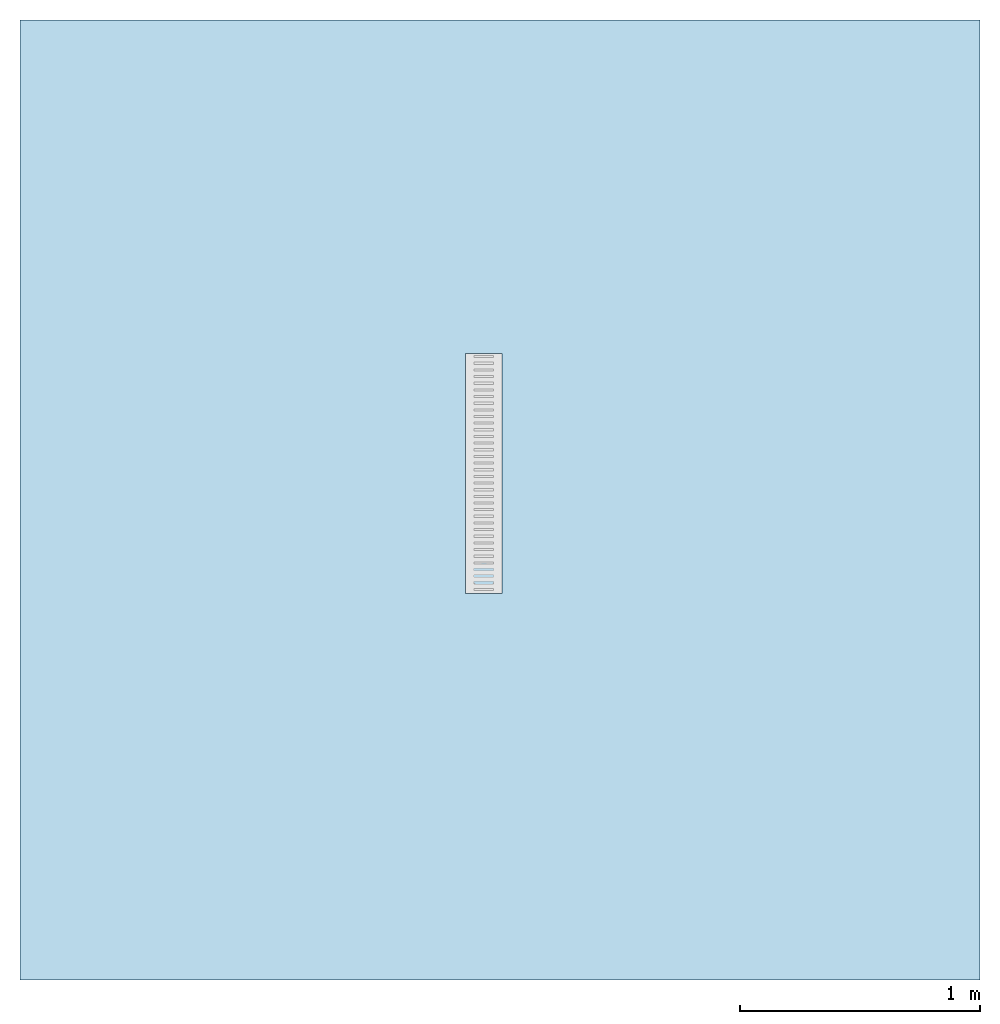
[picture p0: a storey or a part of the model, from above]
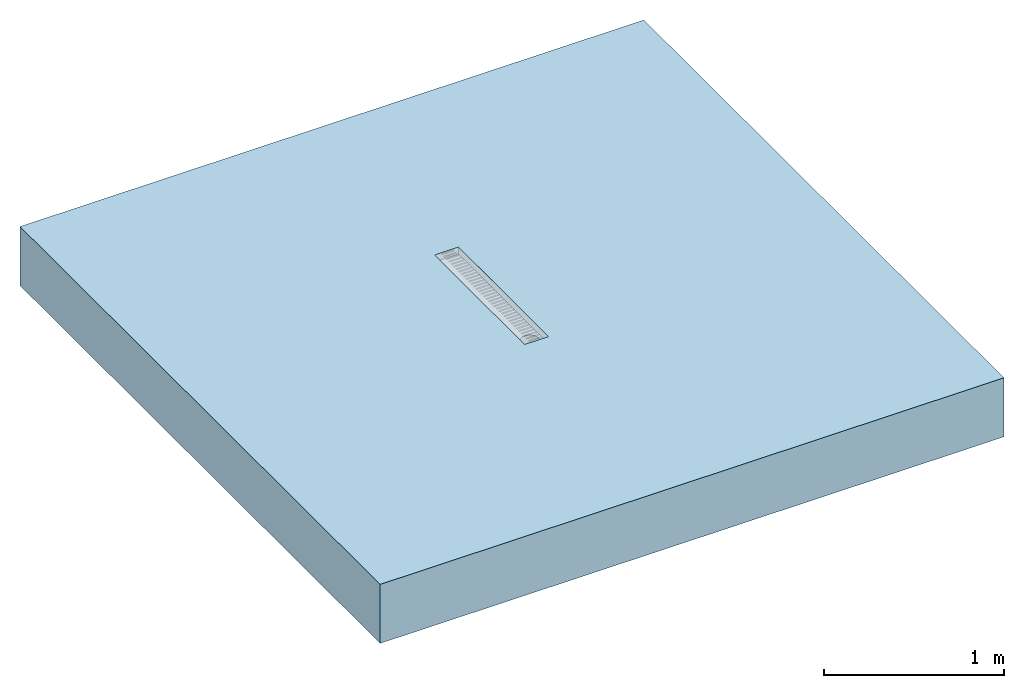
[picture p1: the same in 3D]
Properties of the parts of a building model (IFC2X3)

# File
Description: ViewDefinition [CoordinationView]
File name: 105264 - Level Outlet Invert Channel-1000mm LG.ifc
Time: 2014-03-20T14:39:26
Written by: Autodesk Revit 2013
Made in: 20120221_2030(x64)

# IfcProject, Project Number
LongName: Project Name; Phase: Project Status

# IfcSite, Default
RefLatitude: 42, 21, 30, 344238; RefLongitude: -71, -3, -35, -194702; RefElevation: 0 mm

# IfcBuilding
Pset_BuildingCommon - NumberOfStoreys: 1
Other - Project Status: Project Status; Client Name: Owner; Project Address: ## Street City, State Zip; Project Number: Project Number; Project Issue Date: Issue Date; Project Name: Project Name

# IfcBuildingStorey, Level 1
LongName: Level 1; Elevation: 0 mm
Constraints - Elevation Base: 0; Elevation: 0 mm
Graphics - Color: 0; Symbol at End 2 Default: yes; Symbol at End 1 Default: no; Symbol: M_Level Head - Circle: M_Level Head - Circle; Line Weight: 1; Line Pattern: Center
Identity Data - Name: Level 1; Structural: no; Building Story: yes
Dimensions - Computation Height: 0 mm

# IfcBuildingElementProxy: 105264 - Level Outlet Invert Channel-1000mm LG, ACO BD Deckline 125 Outlet Unit:105264 - Level Outlet Invert Channel-1000mm LG:105264 - Level Outlet Invert Channel-1000mm LG:222661
In: Level 1
Material: Steel, Galvanized
Dimensions - Length Channel: -997 mm; Neoprene Gasket Start: -997 mm; Endplate Position: 1000 mm; Grating Void Cut Length: 0 mm; Neoprene Gasket End: -1000 mm; Volume: 2782425 mm3
Construction - 105508 - C250 Perforated Grating - 1000mm Long - Galvanized Finish.: no; 105522 - A15 Slotted Grating - 1000mm Long - Galvanized Finish.: no; 105523 - A15 Slotted Grating - 500mm Long - Galvanized Finish.: no; End Plate Invert 2: no; End Plate Invert 1: no; 105525 - C250 Slotted Grating - 500mm Long - Galvanized Finish.: no; 105509 - C250 Perforated Grating - 500mm Long - Galvanized Finish.: no; 15704 - C250 Composite Grating - 500mm Long - Black Colored Finish.: no; 105524 - C250 Slotted Grating - 1000mm Long - Galvanized Finish.: no; Foul Air Trap: no; Sieve: no; 10735 - C250 Composite Grating - 500mm Long - White Colored Finish.: no
Phasing - Phase Created: New Construction
Constraints - Level: Level: Level 1
Pset_BuildingElementProxyCommon - Reference: 105264 - Level Outlet Invert Channel-1000mm LG
General - Product Description: ACO Deckline Level Invert Channel Outlet (1000 Long); Product Code: 105264; Product Standard: BS EN 1433:2002 CE marked; Channel Colour: Galvanised; Load Class: A15 - C250; Channel Material: Hot Dipped Galvanised Steel; Maintenance guidelines: X:\Electronic Literature\Building Drainage Literature\Deckline\Deckline 125.PDF; Seal Recycled Material Content: 0%; Seal Recyclable: Fully recyclable; Seal Material: Neoprene; Dimensions (LxWxH): 1000mm x 153mm x 63mm; Installation guidelines: X:\Electronic Literature\Building Drainage Literature\Deckline\Deckline 125.PDF; Product Type: shallow invert surface water drainage system; Price: POA - contact ACO; Seal Colour: Black; Channel Recycled Material Content: 25 - 30 %; Weight (Kg): 4.2; Product Range: ACO Deckline 125; NBS Specification: NBS Section Q10 Kerbs/edgings/channels/paving accessories, Clause 180 Drainage Channel Systems; Channel Recyclable: Fully recyclable
Model Properties - Grating Product Code 105523: Load Class A15 - Slotted Galvanized Steel - 500mm long - Slot Width 8mm - 1.0kg; Grating Product Code 15704: Load Class C250 - Composite Black - 500mm long - Slot Width 8mm - 1.2kg; Grating Product Code 105525: Load Class C250 - Slotted Galvanized Steel - 500mm long - Slot Width 8mm - 2.3kg; Grating Product Code 105522: Load Class A15 - Slotted Galvanized Steel - 1000mm long - Slot Width 8mm - 2.0kg; Grating Product Code 105524: Load Class C250 - Slotted Galvanized Steel - 1000mm long - Slot Width 8mm - 4.7kg; Grating Product Code 105509: Load Class C250 - Perforated Galvanized Steel - 500mm long - 2.3kg; Grating Product Code 10735: Load Class C250 - Composite White - 500mm long - Slot Width 8mm - 1.2kg; Grating Product Code 105508: Load Class C250 - Perforated Galvanized Steel - 1000mm long - 4.8kg
Identity Data - Cost: 0; Telephone: +44 (0)1462 816666; Website: www.acobd.com; E-mail Technical: abdtechnical@aco.co.uk; Watermark1: This file is the property of ACO Technologies PLC.; Manufacturer: ACO Building Drainage; Address: ACO Business Centre, Caxton Road, Bedford, MK41 0LF; E-mail Sales: abdcommercial@aco.co.uk; Fax: +44 (0)1462 851490; Watermark2: This file is water marked and users are prohibited to reproduce, adapt, distribute this information.; Watermarked By: www.acobd.com; Watermarked With: BIM Manager Premium Suite.

# IfcOpeningElement: Recess
In: Level 1
Phasing - Phase Created: New Construction
Dimensions - Perimeter: 16000 mm; Volume: 6391697667 mm3; Area: 16000000 mm2; Thickness: 400 mm
Constraints - Height Offset From Level: 0 mm; Related to Mass: no; Level: Level: Level 1; Room Bounding: yes
Structural - Structural: no; Enable Analytical Model: no
Analytical Properties - Thermal Resistance (R): 0.382409; Absorptance: 0.1; Thermal mass: 604440; Roughness: 1; Heat Transfer Coefficient (U): 2.615
Construction - Default Thickness: 400 mm; Function: 0
Graphics - Coarse Scale Fill Color: 0
Materials and Finishes - Structural Material: Concrete, Broom Finish

# IfcSlab: Floor:Generic Floor - 400mm, Floor:Generic Floor - 400mm:193825
In: Level 1
PredefinedType: FLOOR; Material: Concrete, Broom Finish 400 mm
Phasing - Phase Created: New Construction
Dimensions - Perimeter: 16000 mm; Volume: 6391697667 mm3; Area: 16000000 mm2; Thickness: 400 mm
Constraints - Height Offset From Level: 0 mm; Related to Mass: no; Level: Level: Level 1; Room Bounding: yes
Structural - Structural: no; Enable Analytical Model: no
Pset_SlabCommon - Reference: Generic Floor - 400mm; IsExternal: no; LoadBearing: yes
Analytical Properties - Thermal Resistance (R): 0.382409; Absorptance: 0.1; Thermal mass: 604440; Roughness: 1; Heat Transfer Coefficient (U): 2.615
Construction - Default Thickness: 400 mm; Function: 0
Graphics - Coarse Scale Fill Color: 0
Materials and Finishes - Structural Material: Concrete, Broom Finish
